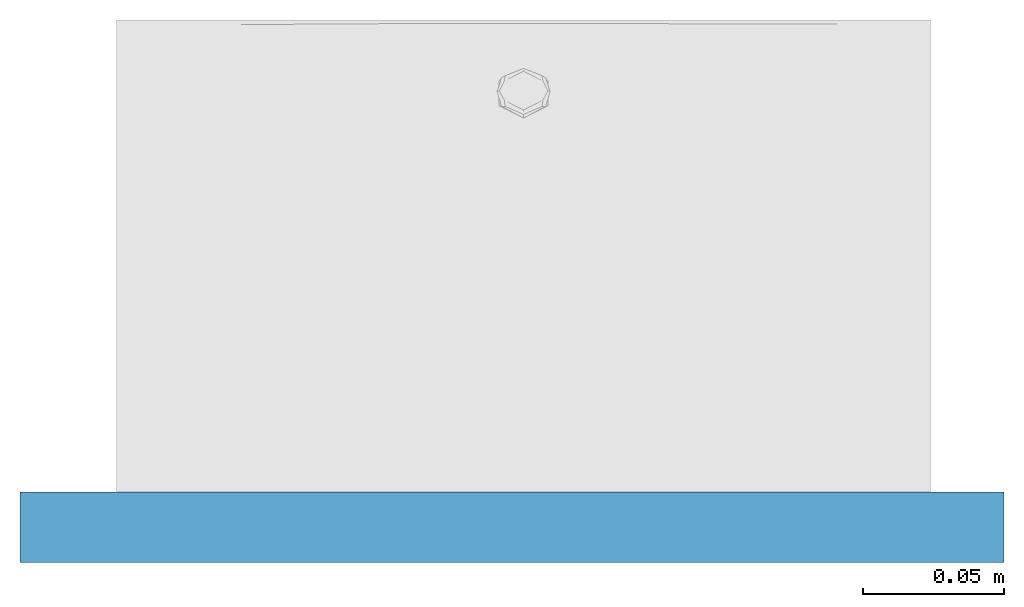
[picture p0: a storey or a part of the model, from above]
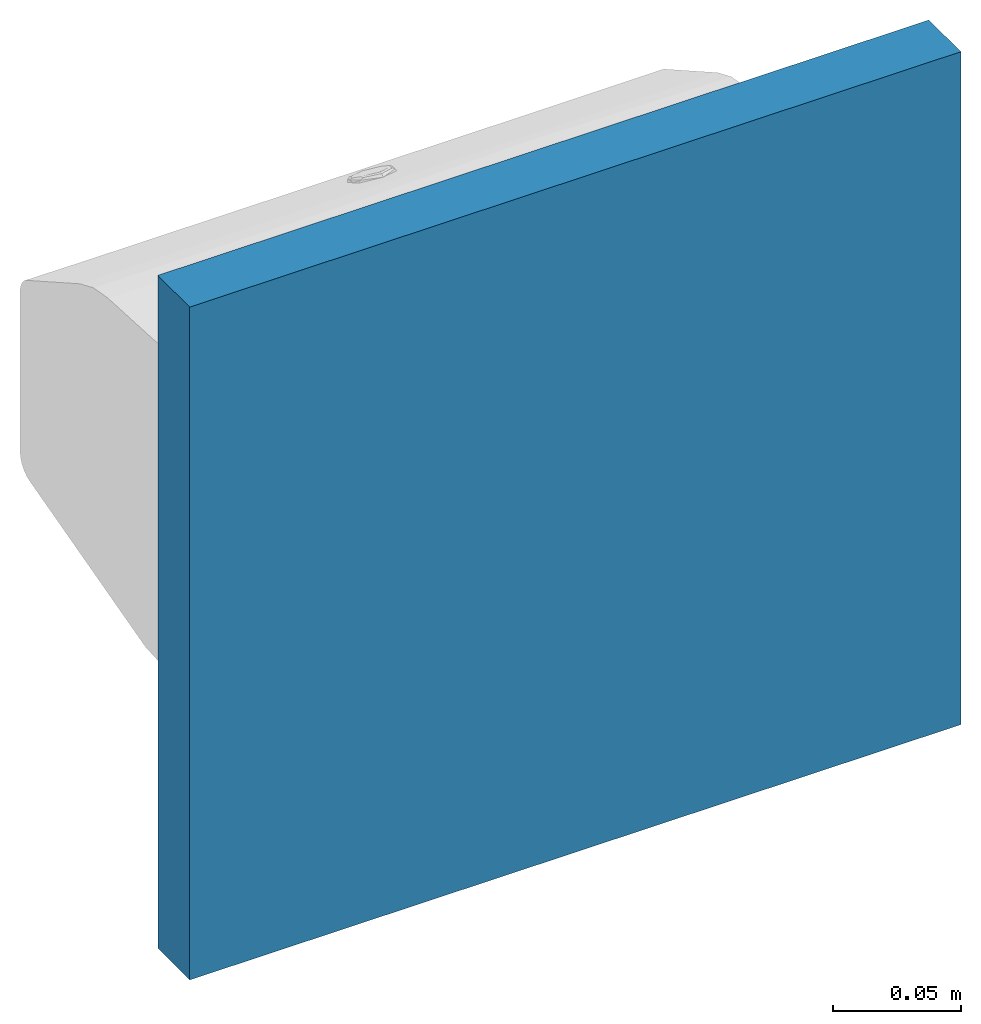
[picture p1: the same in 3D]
Properties of the parts of a building model (IFC2X3)

# File
Description: ViewDefinition [CoordinationView]
Time: 2016-04-01T14:09:29
Written by: The EXPRESS Data Manager Version 5.01.0100.02.64mod : 6 Jun 2012
Made in: 20140709_2115(x64) - Exporter 2014.0.2014.0709 - Default UI
Comment: STEP Physical File produced by: The EXPRESS Data Manager Version 5.01.0100.02.64mod : 6 Jun 2012 * Module: EDMstepFileFactory/EDMstandAlone * Creation date: Fri Apr 01 14:09:29 2016 * Host: BIM-HP * Database: C:\Users\dcole\AppData\Local\Temp\{F4FAE49A-D726-4260-9E29-D56B1C1B3194}\ifc * Database version: 5507 * Database creation date: Fri Apr 01 14:09:26 2016 * Schema: IFC2X3 * Model: DataRepository.ifc * Model creation date: Fri Apr 01 14:09:27 2016 * Header model: DataRepository.ifc_HeaderModel * Header model creation date: Fri Apr 01 14:09:27 2016 * EDMuser: sdai-user * EDMgroup: sdai-group * License ID and type: 5605 : Permanent license. Expiry date: * EDMstepFileFactory options: 020000

# IfcProject
LongName: P:\Fastrack\53721_BELL-CHEM\ADDITIONAL DRAWINGS 2016 BIM\RVT\BC770-10W.ifc

# IfcSite, Default
RefLatitude: 42, 24, 53, 508911; RefLongitude: -71, -15, -29, -58837; RefElevation: 0 mm

# IfcBuilding
Pset_BuildingCommon - NumberOfStoreys: 1

# IfcBuildingStorey, Level 1
LongName: Level 1; Elevation: 0 mm
Constraints - Elevation Base: Project Base Point; Elevation: 0 mm
Identity Data - Structural: no; Name: Level 1; Building Story: yes
Dimensions - Computation Height: 0 mm
Graphics - Color: 0; Symbol at End 1 Default: no; Line Weight: 1; Symbol at End 2 Default: yes; Line Pattern: -3000010

# IfcBuildingElementProxy: BC770-10W Dolphin Couch White Metal Roll Dispenser, BC770-10W:BC770-10W Dolphin Couch White Metal Roll Dispenser:18286
In: Level 1
Material: White Metal
Phasing - Phase Created: New Construction
Dimensions - Volume: 0.000410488 m3; Projection: 122mm; Width: 275mm; Capacity Toilet Roll: 250m; Height: 275mm
Constraints - Elevation: 66.49 mm; Level: Level: Level 1
Pset_ManufacturerTypeInformation - Manufacturer: Bell-Chem Products Co.
Pset_BuildingElementProxyCommon - Reference: BC770-10W Dolphin Couch White Metal Roll Dispenser
Identity Data - Assembly Code: D2010900; Assembly Description: Other Plumbing Fixtures; Description: Mini Jumbo Dispenser; Manufacturer: Bell-Chem Products Co.; Tel No.: +44 (0) 1424 202224; Fax No.: +44 (0) 1424 205200; URL: www.dolphindispensers.co.uk; Model: BC 925; Address line 1: Southpoint, Compass Park, Bodiam, Robertsbridge, TN32 5BS; Email: info@dolphindispensers.co.uk
General - Product Page Link: http://www.dolphindispensers.co.uk/products/bc925-dolphin-stainless-steel-mini-jumbo-dispenser/83.htm; Product Data: Lockable. High quality stainless steel. Full stainless steel back for secure mounting. Inner core diameter: 2.1/4"
Materials and Finishes - Finish: Satin Stainless Steel

# IfcWallStandardCase: Basic Wall:Wall 1, Basic Wall:Wall 1:3092
In: Level 1
Type - PredefinedType: STANDARD; Material: Default Wall 25 mm
Type - Analytical Properties - Absorptance: 0.1; Roughness: 1
Type - Graphics - Coarse Scale Fill Color: 8454143
Type - Construction - Width: 25 mm; Wrapping at Inserts: Do not wrap; Function: Exterior
Constraints - Room Bounding: yes; Top Offset: 0 mm; Base Offset: -22.7478 mm; Top is Attached: no; Base Constraint: Level: Level 1; Related to Mass: no; Location Line: Wall Centerline; Top Extension Distance: 0 mm; Base Extension Distance: 0 mm; Unconnected Height: 321.23 mm; Base is Attached: no
Structural - Enable Analytical Model: no; Structural Usage: Non-bearing; Structural: no
Dimensions - Area: 0.111857 m2; Length: 348.214 mm; Volume: 0.00279642 m3
Phasing - Phase Created: New Construction
Pset_WallCommon - Reference: Wall 1; LoadBearing: no; ExtendToStructure: no; IsExternal: yes
